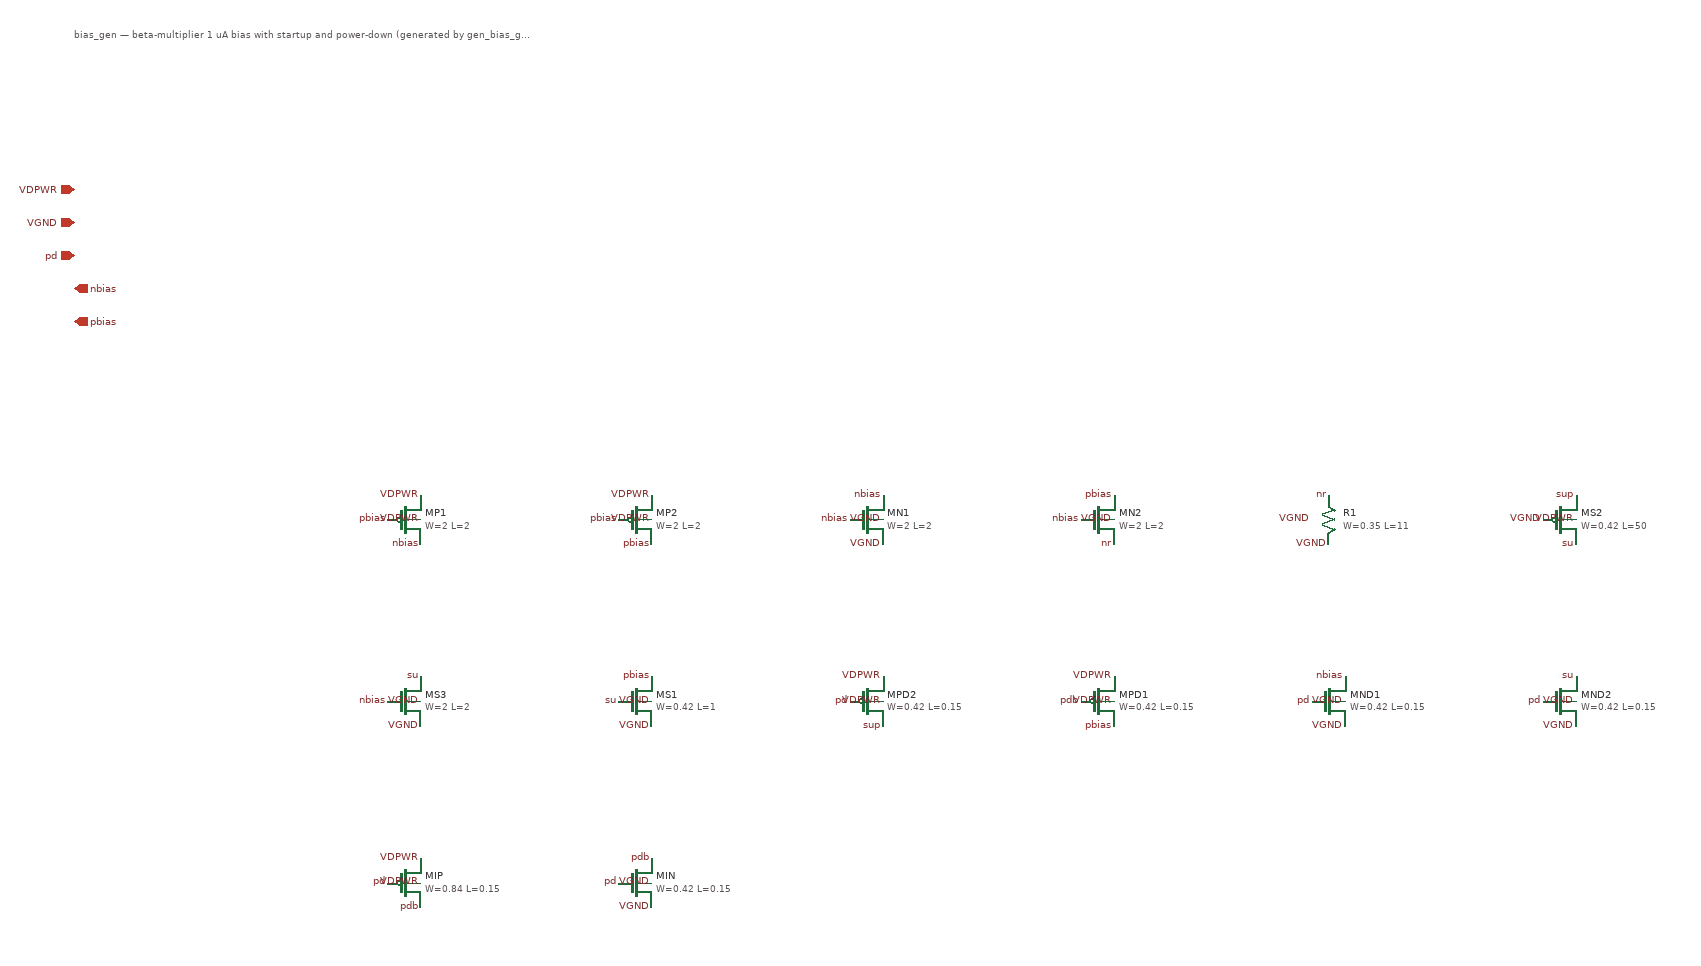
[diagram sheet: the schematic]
v {xschem version=3.4.8RC file_version=1.2}
G {}
K {}
V {}
S {}
E {}
T {bias_gen — beta-multiplier 1 uA bias with startup and power-down (generated by gen_bias_gen.py)} -400 -400 0 0 0.3 0.3 {}
C {iopin.sym} -400 -200 0 0 {name=p_VDPWR lab=VDPWR}
C {iopin.sym} -400 -160 0 0 {name=p_VGND lab=VGND}
C {ipin.sym} -400 -120 0 0 {name=p_pd lab=pd}
C {opin.sym} -400 -80 0 0 {name=p_nbias lab=nbias}
C {opin.sym} -400 -40 0 0 {name=p_pbias lab=pbias}
C {sky130_fd_pr/pfet_01v8_lvt.sym} 0 200 0 0 {name=MP1 model=pfet_01v8_lvt spiceprefix=X W=2 L=2 nf=1 mult=1}
C {lab_pin.sym} 20 230 0 0 {name=p1 sig_type=std_logic lab=nbias}
C {lab_pin.sym} -20 200 0 0 {name=p2 sig_type=std_logic lab=pbias}
C {lab_pin.sym} 20 170 0 0 {name=p3 sig_type=std_logic lab=VDPWR}
C {lab_pin.sym} 20 200 0 0 {name=p4 sig_type=std_logic lab=VDPWR}
C {sky130_fd_pr/pfet_01v8_lvt.sym} 280 200 0 0 {name=MP2 model=pfet_01v8_lvt spiceprefix=X W=2 L=2 nf=1 mult=1}
C {lab_pin.sym} 300 230 0 0 {name=p5 sig_type=std_logic lab=pbias}
C {lab_pin.sym} 260 200 0 0 {name=p6 sig_type=std_logic lab=pbias}
C {lab_pin.sym} 300 170 0 0 {name=p7 sig_type=std_logic lab=VDPWR}
C {lab_pin.sym} 300 200 0 0 {name=p8 sig_type=std_logic lab=VDPWR}
C {sky130_fd_pr/nfet_01v8.sym} 560 200 0 0 {name=MN1 model=nfet_01v8 spiceprefix=X W=2 L=2 nf=1 mult=1}
C {lab_pin.sym} 580 170 0 0 {name=p9 sig_type=std_logic lab=nbias}
C {lab_pin.sym} 540 200 0 0 {name=p10 sig_type=std_logic lab=nbias}
C {lab_pin.sym} 580 230 0 0 {name=p11 sig_type=std_logic lab=VGND}
C {lab_pin.sym} 580 200 0 0 {name=p12 sig_type=std_logic lab=VGND}
C {sky130_fd_pr/nfet_01v8.sym} 840 200 0 0 {name=MN2 model=nfet_01v8 spiceprefix=X W=2 L=2 nf=1 mult=4}
C {lab_pin.sym} 860 170 0 0 {name=p13 sig_type=std_logic lab=pbias}
C {lab_pin.sym} 820 200 0 0 {name=p14 sig_type=std_logic lab=nbias}
C {lab_pin.sym} 860 230 0 0 {name=p15 sig_type=std_logic lab=nr}
C {lab_pin.sym} 860 200 0 0 {name=p16 sig_type=std_logic lab=VGND}
C {sky130_fd_pr/res_xhigh_po_0p35.sym} 1120 200 0 0 {name=R1 W=0.35 L=11 model=res_xhigh_po_0p35 spiceprefix=X mult=1}
C {lab_pin.sym} 1120 170 0 0 {name=p17 sig_type=std_logic lab=nr}
C {lab_pin.sym} 1120 230 0 0 {name=p18 sig_type=std_logic lab=VGND}
C {lab_pin.sym} 1100 200 0 0 {name=p19 sig_type=std_logic lab=VGND}
C {sky130_fd_pr/pfet_01v8.sym} 1400 200 0 0 {name=MS2 model=pfet_01v8 spiceprefix=X W=0.42 L=50 nf=1 mult=1}
C {lab_pin.sym} 1420 230 0 0 {name=p20 sig_type=std_logic lab=su}
C {lab_pin.sym} 1380 200 0 0 {name=p21 sig_type=std_logic lab=VGND}
C {lab_pin.sym} 1420 170 0 0 {name=p22 sig_type=std_logic lab=sup}
C {lab_pin.sym} 1420 200 0 0 {name=p23 sig_type=std_logic lab=VDPWR}
C {sky130_fd_pr/nfet_01v8.sym} 0 420 0 0 {name=MS3 model=nfet_01v8 spiceprefix=X W=2 L=2 nf=1 mult=1}
C {lab_pin.sym} 20 390 0 0 {name=p24 sig_type=std_logic lab=su}
C {lab_pin.sym} -20 420 0 0 {name=p25 sig_type=std_logic lab=nbias}
C {lab_pin.sym} 20 450 0 0 {name=p26 sig_type=std_logic lab=VGND}
C {lab_pin.sym} 20 420 0 0 {name=p27 sig_type=std_logic lab=VGND}
C {sky130_fd_pr/nfet_01v8.sym} 280 420 0 0 {name=MS1 model=nfet_01v8 spiceprefix=X W=0.42 L=1 nf=1 mult=1}
C {lab_pin.sym} 300 390 0 0 {name=p28 sig_type=std_logic lab=pbias}
C {lab_pin.sym} 260 420 0 0 {name=p29 sig_type=std_logic lab=su}
C {lab_pin.sym} 300 450 0 0 {name=p30 sig_type=std_logic lab=VGND}
C {lab_pin.sym} 300 420 0 0 {name=p31 sig_type=std_logic lab=VGND}
C {sky130_fd_pr/pfet_01v8.sym} 560 420 0 0 {name=MPD2 model=pfet_01v8 spiceprefix=X W=0.42 L=0.15 nf=1 mult=1}
C {lab_pin.sym} 580 450 0 0 {name=p32 sig_type=std_logic lab=sup}
C {lab_pin.sym} 540 420 0 0 {name=p33 sig_type=std_logic lab=pd}
C {lab_pin.sym} 580 390 0 0 {name=p34 sig_type=std_logic lab=VDPWR}
C {lab_pin.sym} 580 420 0 0 {name=p35 sig_type=std_logic lab=VDPWR}
C {sky130_fd_pr/pfet_01v8.sym} 840 420 0 0 {name=MPD1 model=pfet_01v8 spiceprefix=X W=0.42 L=0.15 nf=1 mult=1}
C {lab_pin.sym} 860 450 0 0 {name=p36 sig_type=std_logic lab=pbias}
C {lab_pin.sym} 820 420 0 0 {name=p37 sig_type=std_logic lab=pdb}
C {lab_pin.sym} 860 390 0 0 {name=p38 sig_type=std_logic lab=VDPWR}
C {lab_pin.sym} 860 420 0 0 {name=p39 sig_type=std_logic lab=VDPWR}
C {sky130_fd_pr/nfet_01v8.sym} 1120 420 0 0 {name=MND1 model=nfet_01v8 spiceprefix=X W=0.42 L=0.15 nf=1 mult=1}
C {lab_pin.sym} 1140 390 0 0 {name=p40 sig_type=std_logic lab=nbias}
C {lab_pin.sym} 1100 420 0 0 {name=p41 sig_type=std_logic lab=pd}
C {lab_pin.sym} 1140 450 0 0 {name=p42 sig_type=std_logic lab=VGND}
C {lab_pin.sym} 1140 420 0 0 {name=p43 sig_type=std_logic lab=VGND}
C {sky130_fd_pr/nfet_01v8.sym} 1400 420 0 0 {name=MND2 model=nfet_01v8 spiceprefix=X W=0.42 L=0.15 nf=1 mult=1}
C {lab_pin.sym} 1420 390 0 0 {name=p44 sig_type=std_logic lab=su}
C {lab_pin.sym} 1380 420 0 0 {name=p45 sig_type=std_logic lab=pd}
C {lab_pin.sym} 1420 450 0 0 {name=p46 sig_type=std_logic lab=VGND}
C {lab_pin.sym} 1420 420 0 0 {name=p47 sig_type=std_logic lab=VGND}
C {sky130_fd_pr/pfet_01v8.sym} 0 640 0 0 {name=MIP model=pfet_01v8 spiceprefix=X W=0.84 L=0.15 nf=1 mult=1}
C {lab_pin.sym} 20 670 0 0 {name=p48 sig_type=std_logic lab=pdb}
C {lab_pin.sym} -20 640 0 0 {name=p49 sig_type=std_logic lab=pd}
C {lab_pin.sym} 20 610 0 0 {name=p50 sig_type=std_logic lab=VDPWR}
C {lab_pin.sym} 20 640 0 0 {name=p51 sig_type=std_logic lab=VDPWR}
C {sky130_fd_pr/nfet_01v8.sym} 280 640 0 0 {name=MIN model=nfet_01v8 spiceprefix=X W=0.42 L=0.15 nf=1 mult=1}
C {lab_pin.sym} 300 610 0 0 {name=p52 sig_type=std_logic lab=pdb}
C {lab_pin.sym} 260 640 0 0 {name=p53 sig_type=std_logic lab=pd}
C {lab_pin.sym} 300 670 0 0 {name=p54 sig_type=std_logic lab=VGND}
C {lab_pin.sym} 300 640 0 0 {name=p55 sig_type=std_logic lab=VGND}
